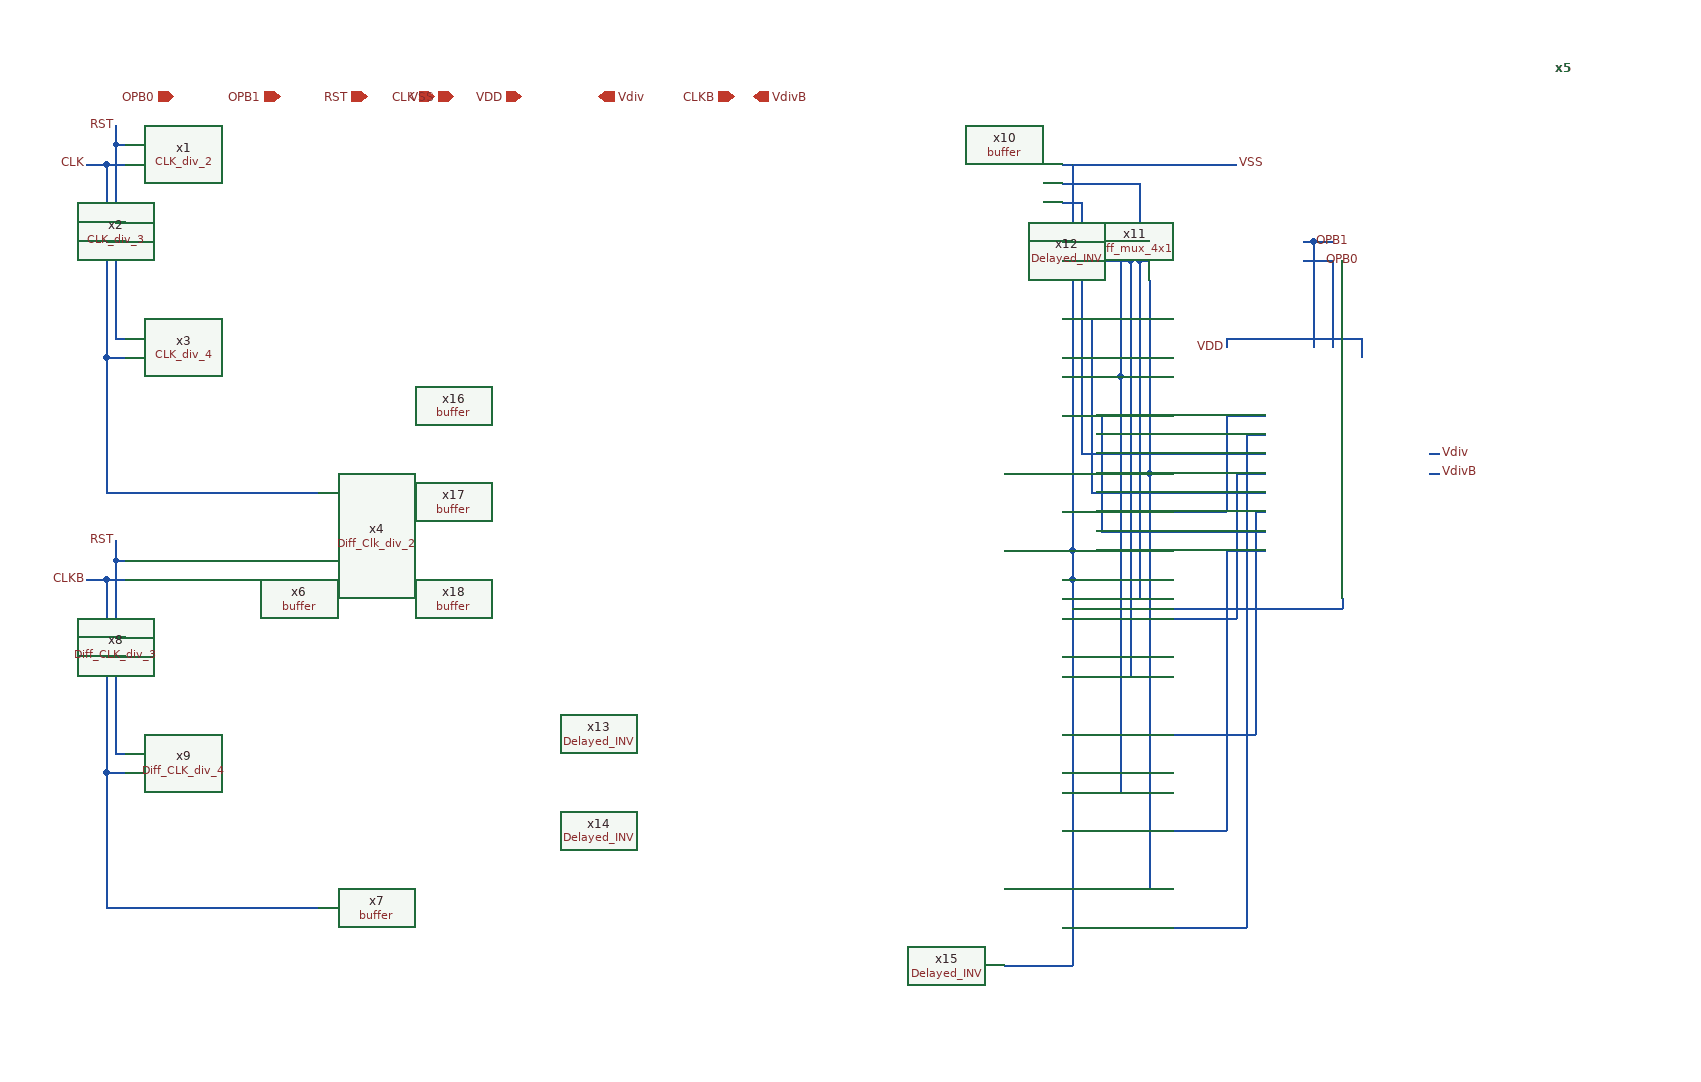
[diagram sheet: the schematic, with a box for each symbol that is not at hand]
v {xschem version=3.1.0 file_version=1.2
}
G {}
K {}
V {}
S {}
E {}
N 580 -540 750 -540 {
lab=VSS}
N 830 -460 840 -460 {
lab=OPB1}
N 750 -360 890 -360 {
lab=VDD}
N 890 -360 890 -340 {
lab=VDD}
N 660 -440 670 -440 {
lab=#net1}
N 660 -520 660 -440 {
lab=#net1}
N 580 -520 660 -520 {
lab=#net1}
N 650 -460 670 -460 {
lab=#net2}
N 580 -440 650 -440 {
lab=#net2}
N 640 -480 670 -480 {
lab=#net3}
N 640 -480 640 -320 {
lab=#net3}
N 580 -320 640 -320 {
lab=#net3}
N 520 -220 670 -220 {
lab=#net4}
N 670 -420 670 -220 {
lab=#net4}
N 590 -540 590 -140 {
lab=VSS}
N 580 -340 590 -340 {
lab=VSS}
N 580 -460 590 -460 {
lab=VSS}
N 780 -280 790 -280 {
lab=#net5}
N 600 -240 790 -240 {
lab=#net6}
N 600 -460 600 -270 {
lab=#net6}
N 580 -500 600 -500 {
lab=#net6}
N 580 -380 610 -380 {
lab=#net7}
N 610 -370 610 -250 {
lab=#net7}
N 610 -200 790 -200 {
lab=#net7}
N 580 -280 620 -280 {
lab=#net8}
N 620 -260 620 -230 {
lab=#net8}
N 620 -160 790 -160 {
lab=#net8}
N -400 -560 -390 -560 {
lab=RST}
N -410 -540 -390 -540 {
lab=CLK}
N -400 -580 -400 -560 {
lab=RST}
N -430 -540 -410 -540 {
lab=CLK}
N -400 -560 -400 -360 {
lab=RST}
N -400 -360 -390 -360 {
lab=RST}
N -400 -480 -390 -480 {
lab=RST}
N -410 -540 -410 -430 {
lab=CLK}
N -410 -460 -390 -460 {
lab=CLK}
N -410 -430 -410 -340 {
lab=CLK}
N -410 -340 -390 -340 {
lab=CLK}
N -410 -340 -410 -200 {
lab=CLK}
N -410 -200 -190 -200 {
lab=CLK}
N 960 -240 970 -240 {
lab=Vdiv}
N 750 -540 760 -540 {
lab=VSS}
N 750 -360 750 -350 {
lab=VDD}
N 840 -460 860 -460 {
lab=OPB1}
N 830 -440 850 -440 {
lab=OPB0}
N 840 -460 840 -350 {
lab=OPB1}
N 860 -440 860 -350 {
lab=OPB0}
N 850 -440 860 -440 {
lab=OPB0}
N 600 -500 600 -460 {
lab=#net6}
N 650 -460 650 -440 {
lab=#net2}
N 610 -380 610 -370 {
lab=#net7}
N 620 -280 620 -260 {
lab=#net8}
N 590 -110 590 290 {
lab=VSS}
N 580 90 590 90 {
lab=VSS}
N 580 -30 590 -30 {
lab=VSS}
N 580 -70 600 -70 {
lab=#net9}
N -400 -130 -390 -130 {
lab=RST}
N -410 -110 -390 -110 {
lab=CLKB}
N -400 -150 -400 -130 {
lab=RST}
N -430 -110 -410 -110 {
lab=CLKB}
N -400 -130 -400 70 {
lab=RST}
N -400 70 -390 70 {
lab=RST}
N -400 -50 -390 -50 {
lab=RST}
N -410 -110 -410 0 {
lab=CLKB}
N -410 -30 -390 -30 {
lab=CLKB}
N -410 0 -410 90 {
lab=CLKB}
N -410 90 -390 90 {
lab=CLKB}
N -410 90 -410 230 {
lab=CLKB}
N -410 230 -190 230 {
lab=CLKB}
N 580 -110 590 -110 {
lab=VSS}
N 590 -140 590 -110 {
lab=VSS}
N 660 -440 660 -90 {
lab=#net1}
N 580 -90 660 -90 {
lab=#net1}
N 650 -440 650 -10 {
lab=#net2}
N 580 -10 650 -10 {
lab=#net2}
N 640 -320 640 110 {
lab=#net3}
N 580 110 640 110 {
lab=#net3}
N 670 -220 670 210 {
lab=#net4}
N 520 210 670 210 {
lab=#net4}
N 520 290 590 290 {
lab=VSS}
N 960 -220 970 -220 {
lab=VdivB}
N 520 -140 590 -140 {
lab=VSS}
N 870 -90 870 -80 {
lab=VSS}
N 590 -80 870 -80 {
lab=VSS}
N 750 -280 750 -180 {
lab=#net5}
N 600 -270 600 -240 {
lab=#net6}
N 610 -250 610 -200 {
lab=#net7}
N 620 -230 620 -160 {
lab=#net8}
N 580 250 770 250 {
lab=#net10}
N 770 -260 770 250 {
lab=#net10}
N 770 -260 790 -260 {
lab=#net10}
N 600 -70 760 -70 {
lab=#net9}
N 760 -220 760 -70 {
lab=#net9}
N 760 -220 790 -220 {
lab=#net9}
N 580 -180 750 -180 {
lab=#net5}
N 750 -280 780 -280 {
lab=#net5}
N 780 -180 790 -180 {
lab=#net11}
N 780 -180 780 50 {
lab=#net11}
N 580 50 780 50 {
lab=#net11}
N 750 -140 790 -140 {
lab=#net12}
N 750 -140 750 150 {
lab=#net12}
N 580 150 750 150 {
lab=#net12}
C {decoder_2x4.sym} 1090 -640 2 0 {name=x5}
C {devices/ipin.sym} -70 -610 0 0 {name=p9 lab=CLK}
C {devices/iopin.sym} -50 -610 0 0 {name=p12 lab=VSS
}
C {devices/iopin.sym} 20 -610 0 0 {name=p13 lab=VDD}
C {devices/ipin.sym} -140 -610 0 0 {name=p30 lab=RST}
C {devices/opin.sym} 100 -610 0 0 {name=p18 lab=Vdiv}
C {devices/ipin.sym} -230 -610 0 0 {name=p4 lab=OPB1}
C {devices/ipin.sym} -340 -610 0 0 {name=p8 lab=OPB0}
C {buffer.sym} -210 -90 0 0 {name=x6}
C {devices/lab_pin.sym} -400 -580 0 0 {name=p5 sig_type=std_logic lab=RST}
C {devices/lab_pin.sym} -430 -540 0 0 {name=p6 sig_type=std_logic lab=CLK}
C {devices/lab_pin.sym} 970 -240 2 0 {name=p7 sig_type=std_logic lab=Vdiv}
C {devices/lab_pin.sym} 760 -540 2 0 {name=p1 sig_type=std_logic lab=VSS}
C {devices/lab_pin.sym} 750 -350 3 0 {name=p2 sig_type=std_logic lab=VDD}
C {devices/lab_pin.sym} 840 -460 2 0 {name=p10 sig_type=std_logic lab=OPB1}
C {devices/lab_pin.sym} 850 -440 2 0 {name=p14 sig_type=std_logic lab=OPB0}
C {CLK_div_2.sym} -240 -540 0 0 {name=x1}
C {CLK_div_3.sym} -240 -440 0 0 {name=x2}
C {CLK_div_4.sym} -240 -330 0 0 {name=x3}
C {buffer.sym} -210 340 0 0 {name=x7}
C {devices/lab_pin.sym} -400 -150 0 0 {name=p3 sig_type=std_logic lab=RST}
C {devices/lab_pin.sym} -430 -110 0 0 {name=p11 sig_type=std_logic lab=CLKB}
C {diff_mux_4x1.sym} 180 20 0 0 {name=x11}
C {devices/lab_pin.sym} 970 -220 2 0 {name=p15 sig_type=std_logic lab=VdivB}
C {devices/ipin.sym} 240 -610 0 0 {name=p16 lab=CLKB}
C {devices/opin.sym} 260 -610 0 0 {name=p17 lab=VdivB}
C {Diff_Clk_div_2.sym} -240 -110 0 0 {name=x4}
C {Diff_CLK_div_3.sym} -240 -10 0 0 {name=x8}
C {Diff_CLK_div_4.sym} -240 100 0 0 {name=x9}
C {buffer.sym} -50 -410 0 0 {name=x10}
C {Delayed_INV.sym} 100 -70 0 0 {name=x12}
C {Delayed_INV.sym} 100 50 0 0 {name=x13}
C {Delayed_INV.sym} 100 150 0 0 {name=x14}
C {Delayed_INV.sym} 100 250 0 0 {name=x15}
C {buffer.sym} -50 -290 0 0 {name=x16}
C {buffer.sym} -50 -190 0 0 {name=x17}
C {buffer.sym} -50 -90 0 0 {name=x18}
